VERSION 5.7 ;
BUSBITCHARS "[]" ;
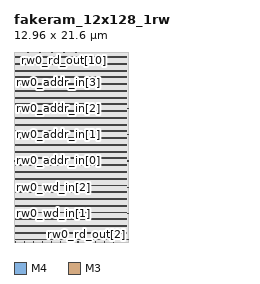
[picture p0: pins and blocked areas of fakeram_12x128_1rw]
MACRO fakeram_12x128_1rw
  FOREIGN fakeram_12x128_1rw 0 0 ;
  SYMMETRY X Y R90 ;
  SIZE 12.960 BY 21.600 ;
  CLASS BLOCK ;
  PIN rw0_wd_in[0]
    DIRECTION INPUT ;
    USE SIGNAL ;
    SHAPE ABUTMENT ;
    PORT
      LAYER M4 ;
      RECT 0.000 0.276 0.072 0.300 ;
    END
  END rw0_wd_in[0]
  PIN rw0_wd_in[1]
    DIRECTION INPUT ;
    USE SIGNAL ;
    SHAPE ABUTMENT ;
    PORT
      LAYER M4 ;
      RECT 0.000 3.252 0.072 3.276 ;
    END
  END rw0_wd_in[1]
  PIN rw0_wd_in[2]
    DIRECTION INPUT ;
    USE SIGNAL ;
    SHAPE ABUTMENT ;
    PORT
      LAYER M4 ;
      RECT 0.000 6.228 0.072 6.252 ;
    END
  END rw0_wd_in[2]
  PIN rw0_wd_in[3]
    DIRECTION INPUT ;
    USE SIGNAL ;
    SHAPE ABUTMENT ;
    PORT
      LAYER M4 ;
      RECT 12.888 0.276 12.960 0.300 ;
    END
  END rw0_wd_in[3]
  PIN rw0_wd_in[4]
    DIRECTION INPUT ;
    USE SIGNAL ;
    SHAPE ABUTMENT ;
    PORT
      LAYER M4 ;
      RECT 12.888 3.252 12.960 3.276 ;
    END
  END rw0_wd_in[4]
  PIN rw0_wd_in[5]
    DIRECTION INPUT ;
    USE SIGNAL ;
    SHAPE ABUTMENT ;
    PORT
      LAYER M4 ;
      RECT 12.888 6.228 12.960 6.252 ;
    END
  END rw0_wd_in[5]
  PIN rw0_wd_in[6]
    DIRECTION INPUT ;
    USE SIGNAL ;
    SHAPE ABUTMENT ;
    PORT
      LAYER M3 ;
      RECT 0.207 0.000 0.225 0.054 ;
    END
  END rw0_wd_in[6]
  PIN rw0_wd_in[7]
    DIRECTION INPUT ;
    USE SIGNAL ;
    SHAPE ABUTMENT ;
    PORT
      LAYER M3 ;
      RECT 1.215 0.000 1.233 0.054 ;
    END
  END rw0_wd_in[7]
  PIN rw0_wd_in[8]
    DIRECTION INPUT ;
    USE SIGNAL ;
    SHAPE ABUTMENT ;
    PORT
      LAYER M3 ;
      RECT 2.223 0.000 2.241 0.054 ;
    END
  END rw0_wd_in[8]
  PIN rw0_wd_in[9]
    DIRECTION INPUT ;
    USE SIGNAL ;
    SHAPE ABUTMENT ;
    PORT
      LAYER M3 ;
      RECT 3.231 0.000 3.249 0.054 ;
    END
  END rw0_wd_in[9]
  PIN rw0_wd_in[10]
    DIRECTION INPUT ;
    USE SIGNAL ;
    SHAPE ABUTMENT ;
    PORT
      LAYER M3 ;
      RECT 4.239 0.000 4.257 0.054 ;
    END
  END rw0_wd_in[10]
  PIN rw0_wd_in[11]
    DIRECTION INPUT ;
    USE SIGNAL ;
    SHAPE ABUTMENT ;
    PORT
      LAYER M3 ;
      RECT 5.247 0.000 5.265 0.054 ;
    END
  END rw0_wd_in[11]
  PIN rw0_rd_out[0]
    DIRECTION OUTPUT ;
    USE SIGNAL ;
    SHAPE ABUTMENT ;
    PORT
      LAYER M3 ;
      RECT 6.255 0.000 6.273 0.054 ;
    END
  END rw0_rd_out[0]
  PIN rw0_rd_out[1]
    DIRECTION OUTPUT ;
    USE SIGNAL ;
    SHAPE ABUTMENT ;
    PORT
      LAYER M3 ;
      RECT 7.263 0.000 7.281 0.054 ;
    END
  END rw0_rd_out[1]
  PIN rw0_rd_out[2]
    DIRECTION OUTPUT ;
    USE SIGNAL ;
    SHAPE ABUTMENT ;
    PORT
      LAYER M3 ;
      RECT 8.271 0.000 8.289 0.054 ;
    END
  END rw0_rd_out[2]
  PIN rw0_rd_out[3]
    DIRECTION OUTPUT ;
    USE SIGNAL ;
    SHAPE ABUTMENT ;
    PORT
      LAYER M3 ;
      RECT 9.279 0.000 9.297 0.054 ;
    END
  END rw0_rd_out[3]
  PIN rw0_rd_out[4]
    DIRECTION OUTPUT ;
    USE SIGNAL ;
    SHAPE ABUTMENT ;
    PORT
      LAYER M3 ;
      RECT 10.287 0.000 10.305 0.054 ;
    END
  END rw0_rd_out[4]
  PIN rw0_rd_out[5]
    DIRECTION OUTPUT ;
    USE SIGNAL ;
    SHAPE ABUTMENT ;
    PORT
      LAYER M3 ;
      RECT 11.295 0.000 11.313 0.054 ;
    END
  END rw0_rd_out[5]
  PIN rw0_rd_out[6]
    DIRECTION OUTPUT ;
    USE SIGNAL ;
    SHAPE ABUTMENT ;
    PORT
      LAYER M3 ;
      RECT 0.207 21.546 0.225 21.600 ;
    END
  END rw0_rd_out[6]
  PIN rw0_rd_out[7]
    DIRECTION OUTPUT ;
    USE SIGNAL ;
    SHAPE ABUTMENT ;
    PORT
      LAYER M3 ;
      RECT 1.575 21.546 1.593 21.600 ;
    END
  END rw0_rd_out[7]
  PIN rw0_rd_out[8]
    DIRECTION OUTPUT ;
    USE SIGNAL ;
    SHAPE ABUTMENT ;
    PORT
      LAYER M3 ;
      RECT 2.943 21.546 2.961 21.600 ;
    END
  END rw0_rd_out[8]
  PIN rw0_rd_out[9]
    DIRECTION OUTPUT ;
    USE SIGNAL ;
    SHAPE ABUTMENT ;
    PORT
      LAYER M3 ;
      RECT 4.311 21.546 4.329 21.600 ;
    END
  END rw0_rd_out[9]
  PIN rw0_rd_out[10]
    DIRECTION OUTPUT ;
    USE SIGNAL ;
    SHAPE ABUTMENT ;
    PORT
      LAYER M3 ;
      RECT 5.679 21.546 5.697 21.600 ;
    END
  END rw0_rd_out[10]
  PIN rw0_rd_out[11]
    DIRECTION OUTPUT ;
    USE SIGNAL ;
    SHAPE ABUTMENT ;
    PORT
      LAYER M3 ;
      RECT 7.047 21.546 7.065 21.600 ;
    END
  END rw0_rd_out[11]
  PIN rw0_addr_in[0]
    DIRECTION INPUT ;
    USE SIGNAL ;
    SHAPE ABUTMENT ;
    PORT
      LAYER M4 ;
      RECT 0.000 9.204 0.072 9.228 ;
    END
  END rw0_addr_in[0]
  PIN rw0_addr_in[1]
    DIRECTION INPUT ;
    USE SIGNAL ;
    SHAPE ABUTMENT ;
    PORT
      LAYER M4 ;
      RECT 0.000 12.180 0.072 12.204 ;
    END
  END rw0_addr_in[1]
  PIN rw0_addr_in[2]
    DIRECTION INPUT ;
    USE SIGNAL ;
    SHAPE ABUTMENT ;
    PORT
      LAYER M4 ;
      RECT 0.000 15.156 0.072 15.180 ;
    END
  END rw0_addr_in[2]
  PIN rw0_addr_in[3]
    DIRECTION INPUT ;
    USE SIGNAL ;
    SHAPE ABUTMENT ;
    PORT
      LAYER M4 ;
      RECT 0.000 18.132 0.072 18.156 ;
    END
  END rw0_addr_in[3]
  PIN rw0_addr_in[4]
    DIRECTION INPUT ;
    USE SIGNAL ;
    SHAPE ABUTMENT ;
    PORT
      LAYER M4 ;
      RECT 12.888 9.204 12.960 9.228 ;
    END
  END rw0_addr_in[4]
  PIN rw0_addr_in[5]
    DIRECTION INPUT ;
    USE SIGNAL ;
    SHAPE ABUTMENT ;
    PORT
      LAYER M4 ;
      RECT 12.888 12.180 12.960 12.204 ;
    END
  END rw0_addr_in[5]
  PIN rw0_addr_in[6]
    DIRECTION INPUT ;
    USE SIGNAL ;
    SHAPE ABUTMENT ;
    PORT
      LAYER M4 ;
      RECT 12.888 15.156 12.960 15.180 ;
    END
  END rw0_addr_in[6]
  PIN rw0_we_in
    DIRECTION INPUT ;
    USE SIGNAL ;
    SHAPE ABUTMENT ;
    PORT
      LAYER M3 ;
      RECT 8.415 21.546 8.433 21.600 ;
    END
  END rw0_we_in
  PIN rw0_ce_in
    DIRECTION INPUT ;
    USE SIGNAL ;
    SHAPE ABUTMENT ;
    PORT
      LAYER M3 ;
      RECT 9.783 21.546 9.801 21.600 ;
    END
  END rw0_ce_in
  PIN rw0_clk
    DIRECTION INPUT ;
    USE SIGNAL ;
    SHAPE ABUTMENT ;
    PORT
      LAYER M3 ;
      RECT 11.151 21.546 11.169 21.600 ;
    END
  END rw0_clk
  PIN VSS
    DIRECTION INOUT ;
    USE GROUND ;
    PORT
      LAYER M4 ;
      RECT 0.216 0.240 12.744 0.336 ;
      RECT 0.216 1.008 12.744 1.104 ;
      RECT 0.216 1.776 12.744 1.872 ;
      RECT 0.216 2.544 12.744 2.640 ;
      RECT 0.216 3.312 12.744 3.408 ;
      RECT 0.216 4.080 12.744 4.176 ;
      RECT 0.216 4.848 12.744 4.944 ;
      RECT 0.216 5.616 12.744 5.712 ;
      RECT 0.216 6.384 12.744 6.480 ;
      RECT 0.216 7.152 12.744 7.248 ;
      RECT 0.216 7.920 12.744 8.016 ;
      RECT 0.216 8.688 12.744 8.784 ;
      RECT 0.216 9.456 12.744 9.552 ;
      RECT 0.216 10.224 12.744 10.320 ;
      RECT 0.216 10.992 12.744 11.088 ;
      RECT 0.216 11.760 12.744 11.856 ;
      RECT 0.216 12.528 12.744 12.624 ;
      RECT 0.216 13.296 12.744 13.392 ;
      RECT 0.216 14.064 12.744 14.160 ;
      RECT 0.216 14.832 12.744 14.928 ;
      RECT 0.216 15.600 12.744 15.696 ;
      RECT 0.216 16.368 12.744 16.464 ;
      RECT 0.216 17.136 12.744 17.232 ;
      RECT 0.216 17.904 12.744 18.000 ;
      RECT 0.216 18.672 12.744 18.768 ;
      RECT 0.216 19.440 12.744 19.536 ;
      RECT 0.216 20.208 12.744 20.304 ;
      RECT 0.216 20.976 12.744 21.072 ;
    END
  END VSS
  PIN VDD
    DIRECTION INOUT ;
    USE POWER ;
    PORT
      LAYER M4 ;
      RECT 0.216 0.240 12.744 0.336 ;
      RECT 0.216 1.008 12.744 1.104 ;
      RECT 0.216 1.776 12.744 1.872 ;
      RECT 0.216 2.544 12.744 2.640 ;
      RECT 0.216 3.312 12.744 3.408 ;
      RECT 0.216 4.080 12.744 4.176 ;
      RECT 0.216 4.848 12.744 4.944 ;
      RECT 0.216 5.616 12.744 5.712 ;
      RECT 0.216 6.384 12.744 6.480 ;
      RECT 0.216 7.152 12.744 7.248 ;
      RECT 0.216 7.920 12.744 8.016 ;
      RECT 0.216 8.688 12.744 8.784 ;
      RECT 0.216 9.456 12.744 9.552 ;
      RECT 0.216 10.224 12.744 10.320 ;
      RECT 0.216 10.992 12.744 11.088 ;
      RECT 0.216 11.760 12.744 11.856 ;
      RECT 0.216 12.528 12.744 12.624 ;
      RECT 0.216 13.296 12.744 13.392 ;
      RECT 0.216 14.064 12.744 14.160 ;
      RECT 0.216 14.832 12.744 14.928 ;
      RECT 0.216 15.600 12.744 15.696 ;
      RECT 0.216 16.368 12.744 16.464 ;
      RECT 0.216 17.136 12.744 17.232 ;
      RECT 0.216 17.904 12.744 18.000 ;
      RECT 0.216 18.672 12.744 18.768 ;
      RECT 0.216 19.440 12.744 19.536 ;
      RECT 0.216 20.208 12.744 20.304 ;
      RECT 0.216 20.976 12.744 21.072 ;
    END
  END VDD
  OBS
    LAYER M1 ;
    RECT 0 0 12.960 21.600 ;
    LAYER M2 ;
    RECT 0 0 12.960 21.600 ;
    LAYER M3 ;
    RECT 0 0 12.960 21.600 ;
    LAYER M4 ;
    RECT 0 0 12.960 21.600 ;
  END
END fakeram_12x128_1rw

END LIBRARY
